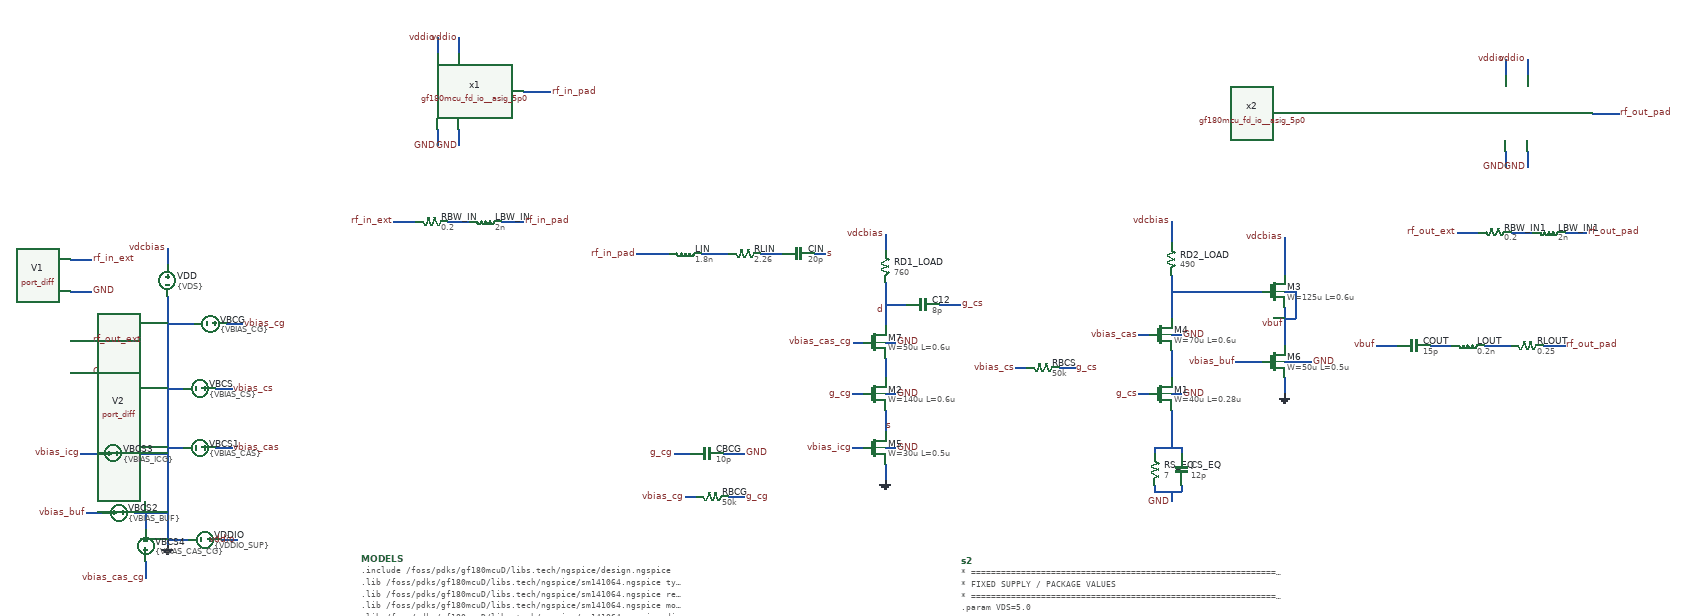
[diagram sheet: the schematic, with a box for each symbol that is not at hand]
v {xschem version=3.4.5 file_version=1.2
}
G {}
K {}
V {}
S {}
E {}
N -320 -440 -320 -410 {
lab=GND}
N 1010 -260 1030 -260 {
lab=GND}
N -320 -410 -320 -310 {
lab=GND}
N -320 -530 -320 -500 {
lab=vdcbias}
N -320 -390 -270 -390 {
lab=GND}
N -500 -510 -460 -510 {
lab=rf_in_ext}
N -500 -450 -460 -450 {
lab=GND}
N -500 -360 -460 -360 {
lab=rf_out_ext}
N -500 -300 -460 -300 {
lab=GND}
N 1010 -466.25 1010 -386.25 {
lab=d}
N 1010 -556.25 1010 -526.25 {
lab=vdcbias}
N -210 -390 -180 -390 {
lab=vbias_cg}
N 880 -520 900 -520 {
lab=s}
N 550 -520 580 -520 {
lab=rf_in_pad}
N 1010 -426.25 1050 -426.25 {
lab=d}
N 1110 -426.25 1150 -426.25 {
lab=g_cs}
N 1010 -230 1010 -220 {
lab=s}
N 1010 -220 1010 -190 {
lab=s}
N 950 -260 970 -260 {
lab=g_cg}
N -320 -310 -320 -110 {
lab=GND}
N 640 -70 660 -70 {
lab=vbias_cg}
N 720 -70 750 -70 {
lab=g_cg}
N 620 -150 650 -150 {
lab=g_cg}
N 710 -150 750 -150 {
lab=GND}
N 300 -580 340 -580 {
lab=rf_in_pad}
N 200 -580 240 -580 {
lab=#net1}
N 100 -580 140 -580 {
lab=rf_in_ext}
N 340 -820 390 -820 {
lab=rf_in_pad}
N 180 -750 180 -720 {
lab=GND}
N 220 -750 220 -720 {
lab=GND}
N 180 -920 180 -890 {
lab=vddio}
N 220 -920 220 -890 {
lab=vddio}
N -320 -270 -290 -270 {
lab=GND}
N -220 10 -190 10 {
lab=vddio}
N 2320 -780 2370 -780 {
lab=rf_out_pad}
N 2160 -710 2160 -680 {
lab=GND}
N 2200 -710 2200 -680 {
lab=GND}
N 2160 -880 2160 -850 {
lab=vddio}
N 2200 -880 2200 -850 {
lab=vddio}
N 2270 -560 2310 -560 {
lab=rf_out_pad}
N 2170 -560 2210 -560 {
lab=#net2}
N 2070 -560 2110 -560 {
lab=rf_out_ext}
N -320 10 -280 10 {
lab=GND}
N -230 -270 -200 -270 {
lab=vbias_cs}
N 1540 -260 1560 -260 {
lab=GND}
N 1540 -230 1540 -220 {
lab=#net3}
N 1480 -260 1500 -260 {
lab=g_cs}
N 1252.5 -308.75 1272.5 -308.75 {
lab=vbias_cs}
N 1332.5 -308.75 1362.5 -308.75 {
lab=g_cs}
N 1540 -220 1540 -160 {
lab=#net3}
N 1540 -580 1540 -540 {
lab=vdcbias}
N 1750 -550 1750 -480 {
lab=vdcbias}
N 1750 -420 1750 -350 {
lab=vbuf}
N 1750 -290 1750 -260 {
lab=GND}
N 1750 -450 1770 -450 {
lab=vbuf}
N 1920 -350 1960 -350 {
lab=vbuf}
N 2020 -350 2060 -350 {
lab=#net4}
N 2120 -350 2170 -350 {
lab=#net5}
N 2230 -350 2270 -350 {
lab=rf_out_pad}
N 580 -520 610 -520 {
lab=rf_in_pad}
N 670 -520 720 -520 {
lab=#net6}
N 780 -520 820 -520 {
lab=#net7}
N 1540 -370 1560 -370 {
lab=GND}
N 1480 -370 1500 -370 {
lab=vbias_cas}
N 1540 -480 1540 -400 {
lab=#net8}
N -320 -110 -320 20 {
lab=GND}
N -230 -160 -200 -160 {
lab=vbias_cas}
N -320 -160 -290 -160 {
lab=GND}
N 1770 -450 1770 -400 {
lab=vbuf}
N 1750 -400 1770 -400 {
lab=vbuf}
N 1010 -160 1030 -160 {
lab=GND}
N 1010 -130 1010 -120 {
lab=GND}
N 950 -160 970 -160 {
lab=vbias_icg}
N 1010 -120 1010 -100 {
lab=GND}
N 1660 -320 1710 -320 {
lab=vbias_buf}
N 1750 -320 1800 -320 {
lab=GND}
N -470 -40 -440 -40 {
lab=vbias_buf}
N -380 -40 -320 -40 {
lab=GND}
N -480 -150 -450 -150 {
lab=vbias_icg}
N -390 -150 -320 -150 {
lab=GND}
N 1560 -160 1560 -150 {
lab=#net3}
N 1510 -160 1560 -160 {
lab=#net3}
N 1560 -90 1560 -80 {
lab=GND}
N 1510 -80 1560 -80 {
lab=GND}
N 1510 -160 1510 -150 {
lab=#net3}
N 1510 -90 1510 -80 {
lab=GND}
N 1540 -80 1540 -60 {
lab=GND}
N 1670 -450 1710 -450 {
lab=#net8}
N 1010 -356.25 1030 -356.25 {
lab=GND}
N 951.25 -356.25 971.25 -356.25 {
lab=vbias_cas_cg}
N -360 51.25 -360 81.25 {
lab=vbias_cas_cg}
N 1540 -341.25 1540 -288.75 {
lab=#net9}
N 1010 -326.25 1010 -288.75 {
lab=#net10}
N -360 -40 -360 -8.75 {
lab=GND}
N 1540 -450 1670 -450 {
lab=#net8}
C {vsource.sym} -240 -390 1 0 {name=VBCG value=\{VBIAS_CG\} savecurrent=false}
C {gnd.sym} 1010 -100 0 0 {name=l1 lab=GND}
C {vsource.sym} -320 -470 0 0 {name=VDD value=\{VDS\} savecurrent=false}
C {capa.sym} 1080 -426.25 3 0 {name=C12
m=1
value=8p
footprint=1206
device="ceramic capacitor"}
C {lab_pin.sym} 1010 -416.25 0 0 {name=p3 sig_type=std_logic lab=d}
C {lab_pin.sym} -460 -510 2 0 {name=p5 sig_type=std_logic lab=rf_in_ext}
C {lab_pin.sym} -460 -450 2 0 {name=p6 sig_type=std_logic lab=GND

}
C {lab_pin.sym} -460 -300 2 0 {name=p8 sig_type=std_logic lab=GND}
C {capa.sym} 850 -520 3 0 {name=CIN
m=1
value=20p
footprint=1206
device="ceramic capacitor"}
C {gnd.sym} -320 20 0 0 {name=l3 lab=GND}
C {lab_pin.sym} -320 -530 0 0 {name=p10 sig_type=std_logic lab=vdcbias
}
C {lab_pin.sym} -180 -390 2 0 {name=p9 sig_type=std_logic lab=vbias_cg}
C {lab_pin.sym} 1010 -556.25 0 0 {name=p11 sig_type=std_logic lab=vdcbias
}
C {lab_pin.sym} 1150 -426.25 2 0 {name=p14 sig_type=std_logic lab=g_cs}
C {port_diff.sym} -500 -480 0 0 {name=V1 portnum=1 Z0=50 DCval=0 ACmag=1 ACphase=0 TRANval=""}
C {port_diff.sym} -500 -330 0 0 {name=V2 portnum=2 Z0=50 DCval=0 ACmag=1 ACphase=0 TRANval=""}
C {lab_pin.sym} 1010 -200 2 0 {name=p1 sig_type=std_logic lab=s}
C {lab_pin.sym} 1030 -260 2 0 {name=p2 sig_type=std_logic lab=GND}
C {code_shown.sym} 40 45 0 0 {name=MODELS only_toplevel=true
format="tcleval( @value )"
value="
.include /foss/pdks/gf180mcuD/libs.tech/ngspice/design.ngspice

.lib /foss/pdks/gf180mcuD/libs.tech/ngspice/sm141064.ngspice typical
.lib /foss/pdks/gf180mcuD/libs.tech/ngspice/sm141064.ngspice res_typical
.lib /foss/pdks/gf180mcuD/libs.tech/ngspice/sm141064.ngspice moscap_typical
.lib /foss/pdks/gf180mcuD/libs.tech/ngspice/sm141064.ngspice diode_typical

*.include /foss/pdks/gf180mcuD/libs.ref/gf180mcu_fd_io/spice/gf180mcu_fd_io.spice
.include /media/sf_LNA_chipathon/The-Silent-Owl-GF180MCU-WB-LNA/analog_pad_sp_paramerters/xschem/gf180mcu_fd_io__asig_5p0.spice 
"}
C {code.sym} 1152.5 48.75 0 0 {name=s2 only_toplevel=false value="


* =============================================================================
* FIXED SUPPLY / PACKAGE VALUES
* =============================================================================

.param VDS=5.0
.param VDDIO_SUP=5.0
.param L_BW=2n
.param R_BW=0.2


* =============================================================================
* FIXED INPUT NETWORK
* =============================================================================

.param L_IN=1.80n
.param R_L_IN=1.5
.param CIN_VAL=100p
.param C_SH_IN=1f


* =============================================================================
* FIXED XM2 COMMON-GATE INPUT STAGE
* =============================================================================

.param VBIAS_CG=2.00
.param W_CG=140u
.param M_CG=2
.param L_CG=0.60u
.param RD1=760
.param RBIAS_CG=50k
.param CBYP_CG=20p


* =============================================================================
* FIXED MIXED-VOLTAGE XM1/XM4 STAGE
* =============================================================================

.param C12_VAL=33p

.param VBIAS_CS=0.95
.param W_CS=40u
.param M_CS=2
.param L_CS=0.28u
.param RBIAS_CS=50k

.param VBIAS_CAS=3.30
.param W_CAS=70u
.param M_CAS=1
.param L_CAS=0.60u
.param RD2=490

.param RS_EQ=7
.param CSEQ_VAL=12p


* =============================================================================
* FIXED BODY-TIED SOURCE FOLLOWER
* =============================================================================

.param W_SF=125u
.param M_SF=2
.param L_SF=0.60u
.param RG_SF_VAL=0.01


* =============================================================================
* FIXED OUTPUT NETWORK
* =============================================================================

.param COUT_VAL=56p
.param L_OUT=0.20n
.param R_L_OUT=1.5
.param C_SH_OUT=1f


* =============================================================================
* FIXED XM5 COMMON-GATE CURRENT SINK
* =============================================================================

.param VBIAS_ICG=1.55
.param L_BIAS_CG=0.50u
.param W_BIAS_CG=30u
.param M_BIAS_CG=1


* =============================================================================
* FIXED XM6 SOURCE-FOLLOWER CURRENT SINK
* =============================================================================

.param VBIAS_BUF=2.40
.param L_BIAS_SF=0.50u
.param W_BIAS_SF=50u
.param M_BIAS_SF=3


* =============================================================================
* XM7 CG-CASCODE SWEEP PARAMETERS
* =============================================================================

.param VBIAS_CAS_CG=3.40
.param L_CAS_CG=0.60u
.param W_CAS_CG=50u
.param M_CAS_CG=2

.control

set noaskquit
set plotwinsize=0
set numdgt=10


* ============================================================
* RF PERFORMANCE: 1 MHz TO 7 GHz
* ============================================================

sp lin 2801 1Meg 7Gig 1

let FGHz=frequency/1e9

let S11db=db(s_1_1)
let S21db=db(s_2_1)
let S12db=db(s_1_2)
let S22db=db(s_2_2)

let NFdb=real(NF)
let NFMINdb=real(NFmin)

let Delta=s_1_1*s_2_2-s_1_2*s_2_1
let DeltaMag=mag(Delta)

let A11=mag(s_1_1)
let A12=mag(s_1_2)
let A21=mag(s_2_1)
let A22=mag(s_2_2)

let Mu=(1-A11*A11) \\
    /(mag(s_2_2-Delta*conj(s_1_1))+mag(s_1_2*s_2_1))

let Mup=(1-A22*A22) \\
    /(mag(s_1_1-Delta*conj(s_2_2))+mag(s_1_2*s_2_1))

let Kfactor=(1-A11*A11-A22*A22+DeltaMag*DeltaMag) \\
    /(2*A12*A21)

let Zin=50*(1+s_1_1)/(1-s_1_1)
let Zout=50*(1+s_2_2)/(1-s_2_2)

let ZinRe=real(Zin)
let ZinIm=imag(Zin)
let ZoutRe=real(Zout)
let ZoutIm=imag(Zout)

setscale FGHz


* Target-band plots

plot S21db xlimit 2.3 2.5
plot S11db S22db xlimit 2.3 2.5
plot NFdb NFMINdb xlimit 2.3 2.5
plot Mu Mup xlimit 2.3 2.5


* Broadband plots

plot S21db xlimit 0 7
plot S11db S22db xlimit 0 7
plot NFdb NFMINdb xlimit 0 7
plot S12db xlimit 0 7

plot Mu Mup xlimit 0 7
plot Kfactor xlimit 0 7
plot DeltaMag xlimit 0 7

plot ZinRe ZinIm xlimit 0 7
plot ZoutRe ZoutIm xlimit 0 7


* ============================================================
* WIDEBAND STABILITY: 10 MHz TO 30 GHz
* ============================================================

sp dec 100 10Meg 30Gig 1

let WBDelta=s_1_1*s_2_2-s_1_2*s_2_1
let WBDeltaMag=mag(WBDelta)

let WBA11=mag(s_1_1)
let WBA12=mag(s_1_2)
let WBA21=mag(s_2_1)
let WBA22=mag(s_2_2)

let WBMu=(1-WBA11*WBA11) \\
    /(mag(s_2_2-WBDelta*conj(s_1_1))+mag(s_1_2*s_2_1))

let WBMup=(1-WBA22*WBA22) \\
    /(mag(s_1_1-WBDelta*conj(s_2_2))+mag(s_1_2*s_2_1))

let WBK=(1-WBA11*WBA11-WBA22*WBA22+WBDeltaMag*WBDeltaMag) \\
    /(2*WBA12*WBA21)

plot WBMu WBMup
plot WBK
plot WBDeltaMag




.endc


"}
C {symbols/nfet_06v0.sym} 990 -260 0 0 {name=M2
L=0.6u
W=140u
nf=10
m=2
ad="'int((nf+1)/2) * W/nf * 0.18u'"
pd="'2*int((nf+1)/2) * (W/nf + 0.18u)'"
as="'int((nf+2)/2) * W/nf * 0.18u'"
ps="'2*int((nf+2)/2) * (W/nf + 0.18u)'"
nrd="'0.18u / W'" nrs="'0.18u / W'"
sa=0 sb=0 sd=0
model=nfet_06v0
spiceprefix=X
}
C {lab_pin.sym} 900 -520 2 0 {name=p17 sig_type=std_logic lab=s}
C {res.sym} 690 -70 1 0 {name=RBCG
value=50k
footprint=1206
device=resistor
m=1}
C {lab_pin.sym} 640 -70 0 0 {name=p20 sig_type=std_logic lab=vbias_cg}
C {lab_pin.sym} 750 -70 2 0 {name=p21 sig_type=std_logic lab=g_cg}
C {capa.sym} 680 -150 3 0 {name=CBCG
m=1
value=10p
footprint=1206
device="ceramic capacitor"}
C {lab_pin.sym} 750 -150 2 0 {name=p19 sig_type=std_logic lab=GND}
C {/media/sf_LNA_chipathon/The-Silent-Owl-GF180MCU-WB-LNA/analog_pad_sp_paramerters/xschem/gf180mcu_fd_io__asig_5p0.sym} 190 -820 0 0 {name=x1 model=gf180mcu_fd_io__asig_5p0}
C {ind.sym} 270 -580 1 0 {name=LBW_IN
m=1
value=2n
footprint=1206
device=inductor}
C {res.sym} 170 -580 1 0 {name=RBW_IN
value=0.2
footprint=1206
device=resistor
m=1}
C {lab_pin.sym} 100 -580 0 0 {name=p22 sig_type=std_logic lab=rf_in_ext}
C {lab_pin.sym} 340 -580 2 0 {name=p25 sig_type=std_logic lab=rf_in_pad}
C {lab_pin.sym} 390 -820 2 0 {name=p26 sig_type=std_logic lab=rf_in_pad}
C {vsource.sym} -250 10 1 0 {name=VDDIO value=\{VDDIO_SUP\} savecurrent=false}
C {lab_pin.sym} -190 10 1 0 {name=p27 sig_type=std_logic lab=vddio
}
C {lab_pin.sym} 180 -920 1 0 {name=p28 sig_type=std_logic lab=vddio
}
C {lab_pin.sym} 220 -920 1 0 {name=p29 sig_type=std_logic lab=vddio
}
C {lab_pin.sym} 180 -720 3 0 {name=p30 sig_type=std_logic lab=GND}
C {lab_pin.sym} 220 -720 3 0 {name=p31 sig_type=std_logic lab=GND}
C {lab_pin.sym} 550 -520 0 0 {name=p13 sig_type=std_logic lab=rf_in_pad}
C {/media/sf_LNA_chipathon/The-Silent-Owl-GF180MCU-WB-LNA/analog_pad_sp_paramerters/xschem/gf180mcu_fd_io__asig_5p0.sym} 2170 -780 0 0 {name=x2 model=gf180mcu_fd_io__asig_5p0}
C {lab_pin.sym} 2160 -880 1 0 {name=p33 sig_type=std_logic lab=vddio
}
C {lab_pin.sym} 2200 -880 1 0 {name=p34 sig_type=std_logic lab=vddio
}
C {lab_pin.sym} 2160 -680 3 0 {name=p35 sig_type=std_logic lab=GND}
C {lab_pin.sym} 2200 -680 3 0 {name=p36 sig_type=std_logic lab=GND}
C {lab_pin.sym} 2370 -780 2 0 {name=p32 sig_type=std_logic lab=rf_out_pad}
C {ind.sym} 2240 -560 1 0 {name=LBW_IN1
m=1
value=2n
footprint=1206
device=inductor}
C {res.sym} 2140 -560 1 0 {name=RBW_IN1
value=0.2
footprint=1206
device=resistor
m=1}
C {lab_pin.sym} 2070 -560 0 0 {name=p37 sig_type=std_logic lab=rf_out_ext}
C {lab_pin.sym} 2310 -560 2 0 {name=p38 sig_type=std_logic lab=rf_out_pad}
C {lab_pin.sym} -460 -360 2 0 {name=p7 sig_type=std_logic lab=rf_out_ext}
C {vsource.sym} -260 -270 1 0 {name=VBCS value=\{VBIAS_CS\} savecurrent=false}
C {lab_pin.sym} -200 -270 2 0 {name=p12 sig_type=std_logic lab=vbias_cs}
C {lab_pin.sym} 950 -260 0 0 {name=p4 sig_type=std_logic lab=g_cg}
C {lab_pin.sym} 620 -150 0 0 {name=p15 sig_type=std_logic lab=g_cg}
C {res.sym} 1010 -496.25 0 0 {name=RD1_LOAD
value=760
footprint=1206
device=resistor
m=1
}
C {lab_pin.sym} 1540 -60 3 0 {name=p16 sig_type=std_logic lab=GND}
C {lab_pin.sym} 1480 -260 0 0 {name=p18 sig_type=std_logic lab=g_cs}
C {res.sym} 1302.5 -308.75 1 0 {name=RBCS
value=50k
footprint=1206
device=resistor
m=1}
C {lab_pin.sym} 1252.5 -308.75 0 0 {name=p23 sig_type=std_logic lab=vbias_cs}
C {lab_pin.sym} 1362.5 -308.75 2 0 {name=p24 sig_type=std_logic lab=g_cs}
C {res.sym} 1540 -510 0 0 {name=RD2_LOAD
value=490
footprint=1206
device=resistor
m=1
}
C {lab_pin.sym} 1540 -580 0 0 {name=p39 sig_type=std_logic lab=vdcbias
}
C {symbols/nfet_06v0.sym} 1730 -450 0 0 {name=M3
L=0.6u
W=125u
nf=10
m=2
ad="'int((nf+1)/2) * W/nf * 0.18u'"
pd="'2*int((nf+1)/2) * (W/nf + 0.18u)'"
as="'int((nf+2)/2) * W/nf * 0.18u'"
ps="'2*int((nf+2)/2) * (W/nf + 0.18u)'"
nrd="'0.18u / W'" nrs="'0.18u / W'"
sa=0 sb=0 sd=0
model=nfet_06v0
spiceprefix=X
}
C {lab_pin.sym} 1750 -550 0 0 {name=p40 sig_type=std_logic lab=vdcbias
}
C {gnd.sym} 1750 -260 0 0 {name=l2 lab=GND}
C {capa.sym} 1990 -350 3 0 {name=COUT
m=1
value=15p
footprint=1206
device="ceramic capacitor"}
C {lab_pin.sym} 1750 -390 0 0 {name=p43 sig_type=std_logic lab=vbuf}
C {lab_pin.sym} 1920 -350 0 0 {name=p44 sig_type=std_logic lab=vbuf}
C {lab_pin.sym} 2270 -350 2 0 {name=p45 sig_type=std_logic lab=rf_out_pad}
C {ind.sym} 2090 -350 1 0 {name=LOUT
m=1
value=0.2n
footprint=1206
device=inductor
}
C {res.sym} 2200 -350 1 0 {name=RLOUT
value=0.25
footprint=1206
device=resistor
m=1}
C {ind.sym} 640 -520 1 0 {name=LIN
m=1
value=1.8n
footprint=1206
device=inductor
}
C {res.sym} 750 -520 1 0 {name=RLIN
value=2.26
footprint=1206
device=resistor
m=1}
C {symbols/nfet_06v0.sym} 1520 -370 0 0 {name=M4
L=0.6u
W=70u
nf=10
m=1
ad="'int((nf+1)/2) * W/nf * 0.18u'"
pd="'2*int((nf+1)/2) * (W/nf + 0.18u)'"
as="'int((nf+2)/2) * W/nf * 0.18u'"
ps="'2*int((nf+2)/2) * (W/nf + 0.18u)'"
nrd="'0.18u / W'" nrs="'0.18u / W'"
sa=0 sb=0 sd=0
model=nfet_06v0
spiceprefix=X
}
C {lab_pin.sym} 1480 -370 0 0 {name=p47 sig_type=std_logic lab=vbias_cas}
C {lab_pin.sym} 1560 -370 2 0 {name=p48 sig_type=std_logic lab=GND}
C {vsource.sym} -260 -160 1 0 {name=VBCS1 value=\{VBIAS_CAS\} savecurrent=false}
C {lab_pin.sym} -200 -160 2 0 {name=p49 sig_type=std_logic lab=vbias_cas}
C {lab_pin.sym} 1030 -160 2 0 {name=p41 sig_type=std_logic lab=GND}
C {lab_pin.sym} 950 -160 0 0 {name=p50 sig_type=std_logic lab=vbias_icg}
C {lab_pin.sym} 1660 -320 0 0 {name=p51 sig_type=std_logic lab=vbias_buf}
C {lab_pin.sym} 1800 -320 2 0 {name=p52 sig_type=std_logic lab=GND}
C {vsource.sym} -410 -40 3 0 {name=VBCS2 value=\{VBIAS_BUF\} savecurrent=false}
C {lab_pin.sym} -470 -40 0 0 {name=p53 sig_type=std_logic lab=vbias_buf}
C {vsource.sym} -420 -150 3 0 {name=VBCS3 value=\{VBIAS_ICG\} savecurrent=false}
C {lab_pin.sym} -480 -150 0 0 {name=p54 sig_type=std_logic lab=vbias_icg}
C {symbols/nfet_03v3.sym} 990 -160 0 0 {name=M5
L=0.5u
W=30u
nf=10
m=1
ad="'int((nf+1)/2) * W/nf * 0.18u'"
pd="'2*int((nf+1)/2) * (W/nf + 0.18u)'"
as="'int((nf+2)/2) * W/nf * 0.18u'"
ps="'2*int((nf+2)/2) * (W/nf + 0.18u)'"
nrd="'0.18u / W'" nrs="'0.18u / W'"
sa=0 sb=0 sd=0
model=nfet_03v3
spiceprefix=X
}
C {symbols/nfet_03v3.sym} 1730 -320 0 0 {name=M6
L=0.5u
W=50u
nf=10
m=3
ad="'int((nf+1)/2) * W/nf * 0.18u'"
pd="'2*int((nf+1)/2) * (W/nf + 0.18u)'"
as="'int((nf+2)/2) * W/nf * 0.18u'"
ps="'2*int((nf+2)/2) * (W/nf + 0.18u)'"
nrd="'0.18u / W'" nrs="'0.18u / W'"
sa=0 sb=0 sd=0
model=nfet_03v3
spiceprefix=X
}
C {res.sym} 1510 -120 0 0 {name=RS_EQ
value=7
footprint=1206
device=resistor
m=1
}
C {capa.sym} 1560 -120 0 0 {name=CS_EQ
m=1
value=12p
footprint=1206
device="ceramic capacitor"}
C {lab_pin.sym} 1560 -260 2 0 {name=p55 sig_type=std_logic lab=GND}
C {symbols/nfet_03v3.sym} 1520 -260 0 0 {name=M1
L=0.28u
W=40u
nf=10
m=2
ad="'int((nf+1)/2) * W/nf * 0.18u'"
pd="'2*int((nf+1)/2) * (W/nf + 0.18u)'"
as="'int((nf+2)/2) * W/nf * 0.18u'"
ps="'2*int((nf+2)/2) * (W/nf + 0.18u)'"
nrd="'0.18u / W'" nrs="'0.18u / W'"
sa=0 sb=0 sd=0
model=nfet_03v3
spiceprefix=X
}
C {lab_pin.sym} 1030 -356.25 2 0 {name=p56 sig_type=std_logic lab=GND}
C {lab_pin.sym} 951.25 -356.25 0 0 {name=p57 sig_type=std_logic lab=vbias_cas_cg}
C {vsource.sym} -360 21.25 2 0 {name=VBCS4 value=\{VBIAS_CAS_CG\} savecurrent=false}
C {lab_pin.sym} -360 81.25 3 0 {name=p58 sig_type=std_logic lab=vbias_cas_cg}
C {symbols/nfet_06v0.sym} 990 -356.25 0 0 {name=M7
L=0.6u
W=50u
nf=10
m=2
ad="'int((nf+1)/2) * W/nf * 0.18u'"
pd="'2*int((nf+1)/2) * (W/nf + 0.18u)'"
as="'int((nf+2)/2) * W/nf * 0.18u'"
ps="'2*int((nf+2)/2) * (W/nf + 0.18u)'"
nrd="'0.18u / W'" nrs="'0.18u / W'"
sa=0 sb=0 sd=0
model=nfet_06v0
spiceprefix=X
}
